##
## LEF for PtnCells ;
## created by Innovus v15.23-s045_1 on Sat Mar 22 12:44:48 2025
##

VERSION 5.8 ;

BUSBITCHARS "[]" ;
DIVIDERCHAR "/" ;

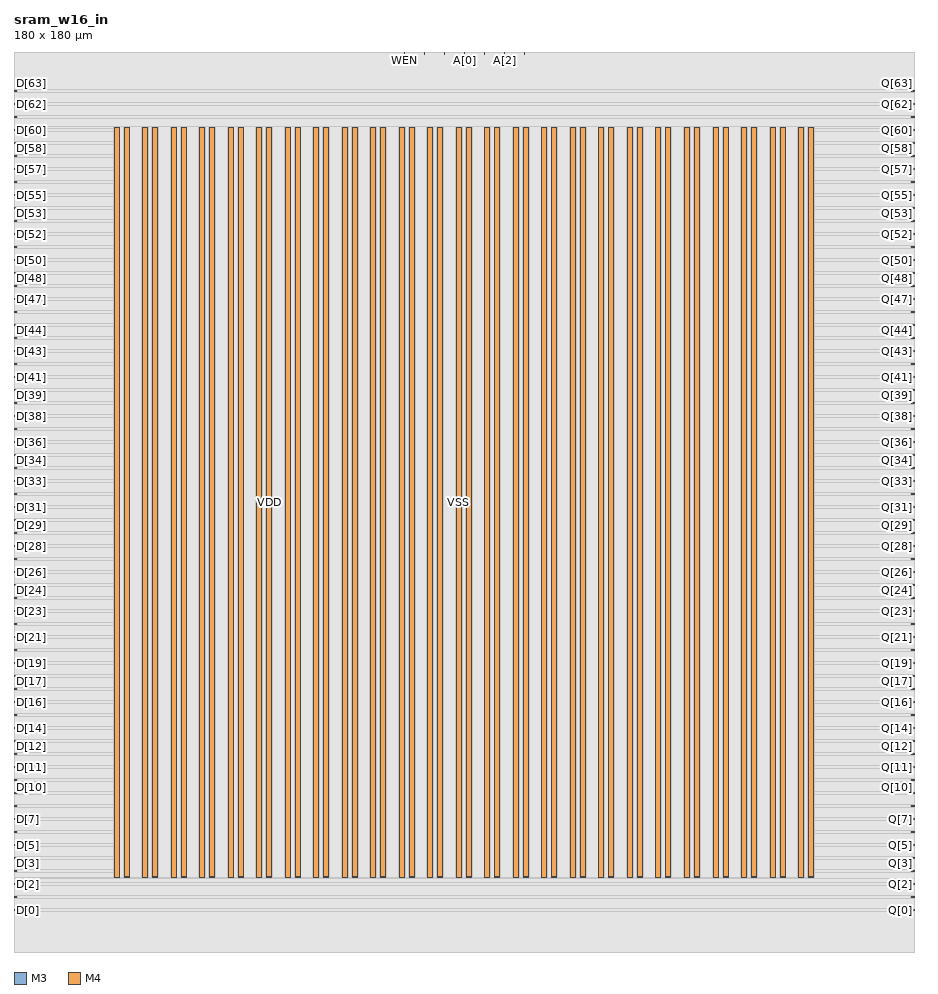
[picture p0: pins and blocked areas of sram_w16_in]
MACRO sram_w16_in
  CLASS BLOCK ;
  SIZE 180.0000 BY 180.0000 ;
  FOREIGN sram_w16_in 0.0000 0.0000 ;
  ORIGIN 0 0 ;
  SYMMETRY X Y R90 ;
  PIN clk
    DIRECTION INPUT ;
    USE SIGNAL ;
    PORT
      LAYER M3 ;
        RECT 82.0500 179.4800 82.1500 180.0000 ;
    END
  END clk
  PIN D[63]
    DIRECTION INPUT ;
    USE SIGNAL ;
    PORT
      LAYER M4 ;
        RECT 0.0000 172.1500 0.5200 172.2500 ;
    END
  END D[63]
  PIN D[62]
    DIRECTION INPUT ;
    USE SIGNAL ;
    PORT
      LAYER M4 ;
        RECT 0.0000 169.5500 0.5200 169.6500 ;
    END
  END D[62]
  PIN D[61]
    DIRECTION INPUT ;
    USE SIGNAL ;
    PORT
      LAYER M4 ;
        RECT 0.0000 166.9500 0.5200 167.0500 ;
    END
  END D[61]
  PIN D[60]
    DIRECTION INPUT ;
    USE SIGNAL ;
    PORT
      LAYER M4 ;
        RECT 0.0000 164.3500 0.5200 164.4500 ;
    END
  END D[60]
  PIN D[59]
    DIRECTION INPUT ;
    USE SIGNAL ;
    PORT
      LAYER M4 ;
        RECT 0.0000 161.7500 0.5200 161.8500 ;
    END
  END D[59]
  PIN D[58]
    DIRECTION INPUT ;
    USE SIGNAL ;
    PORT
      LAYER M4 ;
        RECT 0.0000 159.1500 0.5200 159.2500 ;
    END
  END D[58]
  PIN D[57]
    DIRECTION INPUT ;
    USE SIGNAL ;
    PORT
      LAYER M4 ;
        RECT 0.0000 156.5500 0.5200 156.6500 ;
    END
  END D[57]
  PIN D[56]
    DIRECTION INPUT ;
    USE SIGNAL ;
    PORT
      LAYER M4 ;
        RECT 0.0000 153.9500 0.5200 154.0500 ;
    END
  END D[56]
  PIN D[55]
    DIRECTION INPUT ;
    USE SIGNAL ;
    PORT
      LAYER M4 ;
        RECT 0.0000 151.3500 0.5200 151.4500 ;
    END
  END D[55]
  PIN D[54]
    DIRECTION INPUT ;
    USE SIGNAL ;
    PORT
      LAYER M4 ;
        RECT 0.0000 148.7500 0.5200 148.8500 ;
    END
  END D[54]
  PIN D[53]
    DIRECTION INPUT ;
    USE SIGNAL ;
    PORT
      LAYER M4 ;
        RECT 0.0000 146.1500 0.5200 146.2500 ;
    END
  END D[53]
  PIN D[52]
    DIRECTION INPUT ;
    USE SIGNAL ;
    PORT
      LAYER M4 ;
        RECT 0.0000 143.5500 0.5200 143.6500 ;
    END
  END D[52]
  PIN D[51]
    DIRECTION INPUT ;
    USE SIGNAL ;
    PORT
      LAYER M4 ;
        RECT 0.0000 140.9500 0.5200 141.0500 ;
    END
  END D[51]
  PIN D[50]
    DIRECTION INPUT ;
    USE SIGNAL ;
    PORT
      LAYER M4 ;
        RECT 0.0000 138.3500 0.5200 138.4500 ;
    END
  END D[50]
  PIN D[49]
    DIRECTION INPUT ;
    USE SIGNAL ;
    PORT
      LAYER M4 ;
        RECT 0.0000 135.7500 0.5200 135.8500 ;
    END
  END D[49]
  PIN D[48]
    DIRECTION INPUT ;
    USE SIGNAL ;
    PORT
      LAYER M4 ;
        RECT 0.0000 133.1500 0.5200 133.2500 ;
    END
  END D[48]
  PIN D[47]
    DIRECTION INPUT ;
    USE SIGNAL ;
    PORT
      LAYER M4 ;
        RECT 0.0000 130.5500 0.5200 130.6500 ;
    END
  END D[47]
  PIN D[46]
    DIRECTION INPUT ;
    USE SIGNAL ;
    PORT
      LAYER M4 ;
        RECT 0.0000 127.9500 0.5200 128.0500 ;
    END
  END D[46]
  PIN D[45]
    DIRECTION INPUT ;
    USE SIGNAL ;
    PORT
      LAYER M4 ;
        RECT 0.0000 125.3500 0.5200 125.4500 ;
    END
  END D[45]
  PIN D[44]
    DIRECTION INPUT ;
    USE SIGNAL ;
    PORT
      LAYER M4 ;
        RECT 0.0000 122.7500 0.5200 122.8500 ;
    END
  END D[44]
  PIN D[43]
    DIRECTION INPUT ;
    USE SIGNAL ;
    PORT
      LAYER M4 ;
        RECT 0.0000 120.1500 0.5200 120.2500 ;
    END
  END D[43]
  PIN D[42]
    DIRECTION INPUT ;
    USE SIGNAL ;
    PORT
      LAYER M4 ;
        RECT 0.0000 117.5500 0.5200 117.6500 ;
    END
  END D[42]
  PIN D[41]
    DIRECTION INPUT ;
    USE SIGNAL ;
    PORT
      LAYER M4 ;
        RECT 0.0000 114.9500 0.5200 115.0500 ;
    END
  END D[41]
  PIN D[40]
    DIRECTION INPUT ;
    USE SIGNAL ;
    PORT
      LAYER M4 ;
        RECT 0.0000 112.3500 0.5200 112.4500 ;
    END
  END D[40]
  PIN D[39]
    DIRECTION INPUT ;
    USE SIGNAL ;
    PORT
      LAYER M4 ;
        RECT 0.0000 109.7500 0.5200 109.8500 ;
    END
  END D[39]
  PIN D[38]
    DIRECTION INPUT ;
    USE SIGNAL ;
    PORT
      LAYER M4 ;
        RECT 0.0000 107.1500 0.5200 107.2500 ;
    END
  END D[38]
  PIN D[37]
    DIRECTION INPUT ;
    USE SIGNAL ;
    PORT
      LAYER M4 ;
        RECT 0.0000 104.5500 0.5200 104.6500 ;
    END
  END D[37]
  PIN D[36]
    DIRECTION INPUT ;
    USE SIGNAL ;
    PORT
      LAYER M4 ;
        RECT 0.0000 101.9500 0.5200 102.0500 ;
    END
  END D[36]
  PIN D[35]
    DIRECTION INPUT ;
    USE SIGNAL ;
    PORT
      LAYER M4 ;
        RECT 0.0000 99.3500 0.5200 99.4500 ;
    END
  END D[35]
  PIN D[34]
    DIRECTION INPUT ;
    USE SIGNAL ;
    PORT
      LAYER M4 ;
        RECT 0.0000 96.7500 0.5200 96.8500 ;
    END
  END D[34]
  PIN D[33]
    DIRECTION INPUT ;
    USE SIGNAL ;
    PORT
      LAYER M4 ;
        RECT 0.0000 94.1500 0.5200 94.2500 ;
    END
  END D[33]
  PIN D[32]
    DIRECTION INPUT ;
    USE SIGNAL ;
    PORT
      LAYER M4 ;
        RECT 0.0000 91.5500 0.5200 91.6500 ;
    END
  END D[32]
  PIN D[31]
    DIRECTION INPUT ;
    USE SIGNAL ;
    PORT
      LAYER M4 ;
        RECT 0.0000 88.9500 0.5200 89.0500 ;
    END
  END D[31]
  PIN D[30]
    DIRECTION INPUT ;
    USE SIGNAL ;
    PORT
      LAYER M4 ;
        RECT 0.0000 86.3500 0.5200 86.4500 ;
    END
  END D[30]
  PIN D[29]
    DIRECTION INPUT ;
    USE SIGNAL ;
    PORT
      LAYER M4 ;
        RECT 0.0000 83.7500 0.5200 83.8500 ;
    END
  END D[29]
  PIN D[28]
    DIRECTION INPUT ;
    USE SIGNAL ;
    PORT
      LAYER M4 ;
        RECT 0.0000 81.1500 0.5200 81.2500 ;
    END
  END D[28]
  PIN D[27]
    DIRECTION INPUT ;
    USE SIGNAL ;
    PORT
      LAYER M4 ;
        RECT 0.0000 78.5500 0.5200 78.6500 ;
    END
  END D[27]
  PIN D[26]
    DIRECTION INPUT ;
    USE SIGNAL ;
    PORT
      LAYER M4 ;
        RECT 0.0000 75.9500 0.5200 76.0500 ;
    END
  END D[26]
  PIN D[25]
    DIRECTION INPUT ;
    USE SIGNAL ;
    PORT
      LAYER M4 ;
        RECT 0.0000 73.3500 0.5200 73.4500 ;
    END
  END D[25]
  PIN D[24]
    DIRECTION INPUT ;
    USE SIGNAL ;
    PORT
      LAYER M4 ;
        RECT 0.0000 70.7500 0.5200 70.8500 ;
    END
  END D[24]
  PIN D[23]
    DIRECTION INPUT ;
    USE SIGNAL ;
    PORT
      LAYER M4 ;
        RECT 0.0000 68.1500 0.5200 68.2500 ;
    END
  END D[23]
  PIN D[22]
    DIRECTION INPUT ;
    USE SIGNAL ;
    PORT
      LAYER M4 ;
        RECT 0.0000 65.5500 0.5200 65.6500 ;
    END
  END D[22]
  PIN D[21]
    DIRECTION INPUT ;
    USE SIGNAL ;
    PORT
      LAYER M4 ;
        RECT 0.0000 62.9500 0.5200 63.0500 ;
    END
  END D[21]
  PIN D[20]
    DIRECTION INPUT ;
    USE SIGNAL ;
    PORT
      LAYER M4 ;
        RECT 0.0000 60.3500 0.5200 60.4500 ;
    END
  END D[20]
  PIN D[19]
    DIRECTION INPUT ;
    USE SIGNAL ;
    PORT
      LAYER M4 ;
        RECT 0.0000 57.7500 0.5200 57.8500 ;
    END
  END D[19]
  PIN D[18]
    DIRECTION INPUT ;
    USE SIGNAL ;
    PORT
      LAYER M4 ;
        RECT 0.0000 55.1500 0.5200 55.2500 ;
    END
  END D[18]
  PIN D[17]
    DIRECTION INPUT ;
    USE SIGNAL ;
    PORT
      LAYER M4 ;
        RECT 0.0000 52.5500 0.5200 52.6500 ;
    END
  END D[17]
  PIN D[16]
    DIRECTION INPUT ;
    USE SIGNAL ;
    PORT
      LAYER M4 ;
        RECT 0.0000 49.9500 0.5200 50.0500 ;
    END
  END D[16]
  PIN D[15]
    DIRECTION INPUT ;
    USE SIGNAL ;
    PORT
      LAYER M4 ;
        RECT 0.0000 47.3500 0.5200 47.4500 ;
    END
  END D[15]
  PIN D[14]
    DIRECTION INPUT ;
    USE SIGNAL ;
    PORT
      LAYER M4 ;
        RECT 0.0000 44.7500 0.5200 44.8500 ;
    END
  END D[14]
  PIN D[13]
    DIRECTION INPUT ;
    USE SIGNAL ;
    PORT
      LAYER M4 ;
        RECT 0.0000 42.1500 0.5200 42.2500 ;
    END
  END D[13]
  PIN D[12]
    DIRECTION INPUT ;
    USE SIGNAL ;
    PORT
      LAYER M4 ;
        RECT 0.0000 39.5500 0.5200 39.6500 ;
    END
  END D[12]
  PIN D[11]
    DIRECTION INPUT ;
    USE SIGNAL ;
    PORT
      LAYER M4 ;
        RECT 0.0000 36.9500 0.5200 37.0500 ;
    END
  END D[11]
  PIN D[10]
    DIRECTION INPUT ;
    USE SIGNAL ;
    PORT
      LAYER M4 ;
        RECT 0.0000 34.3500 0.5200 34.4500 ;
    END
  END D[10]
  PIN D[9]
    DIRECTION INPUT ;
    USE SIGNAL ;
    PORT
      LAYER M4 ;
        RECT 0.0000 31.7500 0.5200 31.8500 ;
    END
  END D[9]
  PIN D[8]
    DIRECTION INPUT ;
    USE SIGNAL ;
    PORT
      LAYER M4 ;
        RECT 0.0000 29.1500 0.5200 29.2500 ;
    END
  END D[8]
  PIN D[7]
    DIRECTION INPUT ;
    USE SIGNAL ;
    PORT
      LAYER M4 ;
        RECT 0.0000 26.5500 0.5200 26.6500 ;
    END
  END D[7]
  PIN D[6]
    DIRECTION INPUT ;
    USE SIGNAL ;
    PORT
      LAYER M4 ;
        RECT 0.0000 23.9500 0.5200 24.0500 ;
    END
  END D[6]
  PIN D[5]
    DIRECTION INPUT ;
    USE SIGNAL ;
    PORT
      LAYER M4 ;
        RECT 0.0000 21.3500 0.5200 21.4500 ;
    END
  END D[5]
  PIN D[4]
    DIRECTION INPUT ;
    USE SIGNAL ;
    PORT
      LAYER M4 ;
        RECT 0.0000 18.7500 0.5200 18.8500 ;
    END
  END D[4]
  PIN D[3]
    DIRECTION INPUT ;
    USE SIGNAL ;
    PORT
      LAYER M4 ;
        RECT 0.0000 16.1500 0.5200 16.2500 ;
    END
  END D[3]
  PIN D[2]
    DIRECTION INPUT ;
    USE SIGNAL ;
    PORT
      LAYER M4 ;
        RECT 0.0000 13.5500 0.5200 13.6500 ;
    END
  END D[2]
  PIN D[1]
    DIRECTION INPUT ;
    USE SIGNAL ;
    PORT
      LAYER M4 ;
        RECT 0.0000 10.9500 0.5200 11.0500 ;
    END
  END D[1]
  PIN D[0]
    DIRECTION INPUT ;
    USE SIGNAL ;
    PORT
      LAYER M4 ;
        RECT 0.0000 8.3500 0.5200 8.4500 ;
    END
  END D[0]
  PIN Q[63]
    DIRECTION OUTPUT ;
    USE SIGNAL ;
    PORT
      LAYER M4 ;
        RECT 179.4800 172.1500 180.0000 172.2500 ;
    END
  END Q[63]
  PIN Q[62]
    DIRECTION OUTPUT ;
    USE SIGNAL ;
    PORT
      LAYER M4 ;
        RECT 179.4800 169.5500 180.0000 169.6500 ;
    END
  END Q[62]
  PIN Q[61]
    DIRECTION OUTPUT ;
    USE SIGNAL ;
    PORT
      LAYER M4 ;
        RECT 179.4800 166.9500 180.0000 167.0500 ;
    END
  END Q[61]
  PIN Q[60]
    DIRECTION OUTPUT ;
    USE SIGNAL ;
    PORT
      LAYER M4 ;
        RECT 179.4800 164.3500 180.0000 164.4500 ;
    END
  END Q[60]
  PIN Q[59]
    DIRECTION OUTPUT ;
    USE SIGNAL ;
    PORT
      LAYER M4 ;
        RECT 179.4800 161.7500 180.0000 161.8500 ;
    END
  END Q[59]
  PIN Q[58]
    DIRECTION OUTPUT ;
    USE SIGNAL ;
    PORT
      LAYER M4 ;
        RECT 179.4800 159.1500 180.0000 159.2500 ;
    END
  END Q[58]
  PIN Q[57]
    DIRECTION OUTPUT ;
    USE SIGNAL ;
    PORT
      LAYER M4 ;
        RECT 179.4800 156.5500 180.0000 156.6500 ;
    END
  END Q[57]
  PIN Q[56]
    DIRECTION OUTPUT ;
    USE SIGNAL ;
    PORT
      LAYER M4 ;
        RECT 179.4800 153.9500 180.0000 154.0500 ;
    END
  END Q[56]
  PIN Q[55]
    DIRECTION OUTPUT ;
    USE SIGNAL ;
    PORT
      LAYER M4 ;
        RECT 179.4800 151.3500 180.0000 151.4500 ;
    END
  END Q[55]
  PIN Q[54]
    DIRECTION OUTPUT ;
    USE SIGNAL ;
    PORT
      LAYER M4 ;
        RECT 179.4800 148.7500 180.0000 148.8500 ;
    END
  END Q[54]
  PIN Q[53]
    DIRECTION OUTPUT ;
    USE SIGNAL ;
    PORT
      LAYER M4 ;
        RECT 179.4800 146.1500 180.0000 146.2500 ;
    END
  END Q[53]
  PIN Q[52]
    DIRECTION OUTPUT ;
    USE SIGNAL ;
    PORT
      LAYER M4 ;
        RECT 179.4800 143.5500 180.0000 143.6500 ;
    END
  END Q[52]
  PIN Q[51]
    DIRECTION OUTPUT ;
    USE SIGNAL ;
    PORT
      LAYER M4 ;
        RECT 179.4800 140.9500 180.0000 141.0500 ;
    END
  END Q[51]
  PIN Q[50]
    DIRECTION OUTPUT ;
    USE SIGNAL ;
    PORT
      LAYER M4 ;
        RECT 179.4800 138.3500 180.0000 138.4500 ;
    END
  END Q[50]
  PIN Q[49]
    DIRECTION OUTPUT ;
    USE SIGNAL ;
    PORT
      LAYER M4 ;
        RECT 179.4800 135.7500 180.0000 135.8500 ;
    END
  END Q[49]
  PIN Q[48]
    DIRECTION OUTPUT ;
    USE SIGNAL ;
    PORT
      LAYER M4 ;
        RECT 179.4800 133.1500 180.0000 133.2500 ;
    END
  END Q[48]
  PIN Q[47]
    DIRECTION OUTPUT ;
    USE SIGNAL ;
    PORT
      LAYER M4 ;
        RECT 179.4800 130.5500 180.0000 130.6500 ;
    END
  END Q[47]
  PIN Q[46]
    DIRECTION OUTPUT ;
    USE SIGNAL ;
    PORT
      LAYER M4 ;
        RECT 179.4800 127.9500 180.0000 128.0500 ;
    END
  END Q[46]
  PIN Q[45]
    DIRECTION OUTPUT ;
    USE SIGNAL ;
    PORT
      LAYER M4 ;
        RECT 179.4800 125.3500 180.0000 125.4500 ;
    END
  END Q[45]
  PIN Q[44]
    DIRECTION OUTPUT ;
    USE SIGNAL ;
    PORT
      LAYER M4 ;
        RECT 179.4800 122.7500 180.0000 122.8500 ;
    END
  END Q[44]
  PIN Q[43]
    DIRECTION OUTPUT ;
    USE SIGNAL ;
    PORT
      LAYER M4 ;
        RECT 179.4800 120.1500 180.0000 120.2500 ;
    END
  END Q[43]
  PIN Q[42]
    DIRECTION OUTPUT ;
    USE SIGNAL ;
    PORT
      LAYER M4 ;
        RECT 179.4800 117.5500 180.0000 117.6500 ;
    END
  END Q[42]
  PIN Q[41]
    DIRECTION OUTPUT ;
    USE SIGNAL ;
    PORT
      LAYER M4 ;
        RECT 179.4800 114.9500 180.0000 115.0500 ;
    END
  END Q[41]
  PIN Q[40]
    DIRECTION OUTPUT ;
    USE SIGNAL ;
    PORT
      LAYER M4 ;
        RECT 179.4800 112.3500 180.0000 112.4500 ;
    END
  END Q[40]
  PIN Q[39]
    DIRECTION OUTPUT ;
    USE SIGNAL ;
    PORT
      LAYER M4 ;
        RECT 179.4800 109.7500 180.0000 109.8500 ;
    END
  END Q[39]
  PIN Q[38]
    DIRECTION OUTPUT ;
    USE SIGNAL ;
    PORT
      LAYER M4 ;
        RECT 179.4800 107.1500 180.0000 107.2500 ;
    END
  END Q[38]
  PIN Q[37]
    DIRECTION OUTPUT ;
    USE SIGNAL ;
    PORT
      LAYER M4 ;
        RECT 179.4800 104.5500 180.0000 104.6500 ;
    END
  END Q[37]
  PIN Q[36]
    DIRECTION OUTPUT ;
    USE SIGNAL ;
    PORT
      LAYER M4 ;
        RECT 179.4800 101.9500 180.0000 102.0500 ;
    END
  END Q[36]
  PIN Q[35]
    DIRECTION OUTPUT ;
    USE SIGNAL ;
    PORT
      LAYER M4 ;
        RECT 179.4800 99.3500 180.0000 99.4500 ;
    END
  END Q[35]
  PIN Q[34]
    DIRECTION OUTPUT ;
    USE SIGNAL ;
    PORT
      LAYER M4 ;
        RECT 179.4800 96.7500 180.0000 96.8500 ;
    END
  END Q[34]
  PIN Q[33]
    DIRECTION OUTPUT ;
    USE SIGNAL ;
    PORT
      LAYER M4 ;
        RECT 179.4800 94.1500 180.0000 94.2500 ;
    END
  END Q[33]
  PIN Q[32]
    DIRECTION OUTPUT ;
    USE SIGNAL ;
    PORT
      LAYER M4 ;
        RECT 179.4800 91.5500 180.0000 91.6500 ;
    END
  END Q[32]
  PIN Q[31]
    DIRECTION OUTPUT ;
    USE SIGNAL ;
    PORT
      LAYER M4 ;
        RECT 179.4800 88.9500 180.0000 89.0500 ;
    END
  END Q[31]
  PIN Q[30]
    DIRECTION OUTPUT ;
    USE SIGNAL ;
    PORT
      LAYER M4 ;
        RECT 179.4800 86.3500 180.0000 86.4500 ;
    END
  END Q[30]
  PIN Q[29]
    DIRECTION OUTPUT ;
    USE SIGNAL ;
    PORT
      LAYER M4 ;
        RECT 179.4800 83.7500 180.0000 83.8500 ;
    END
  END Q[29]
  PIN Q[28]
    DIRECTION OUTPUT ;
    USE SIGNAL ;
    PORT
      LAYER M4 ;
        RECT 179.4800 81.1500 180.0000 81.2500 ;
    END
  END Q[28]
  PIN Q[27]
    DIRECTION OUTPUT ;
    USE SIGNAL ;
    PORT
      LAYER M4 ;
        RECT 179.4800 78.5500 180.0000 78.6500 ;
    END
  END Q[27]
  PIN Q[26]
    DIRECTION OUTPUT ;
    USE SIGNAL ;
    PORT
      LAYER M4 ;
        RECT 179.4800 75.9500 180.0000 76.0500 ;
    END
  END Q[26]
  PIN Q[25]
    DIRECTION OUTPUT ;
    USE SIGNAL ;
    PORT
      LAYER M4 ;
        RECT 179.4800 73.3500 180.0000 73.4500 ;
    END
  END Q[25]
  PIN Q[24]
    DIRECTION OUTPUT ;
    USE SIGNAL ;
    PORT
      LAYER M4 ;
        RECT 179.4800 70.7500 180.0000 70.8500 ;
    END
  END Q[24]
  PIN Q[23]
    DIRECTION OUTPUT ;
    USE SIGNAL ;
    PORT
      LAYER M4 ;
        RECT 179.4800 68.1500 180.0000 68.2500 ;
    END
  END Q[23]
  PIN Q[22]
    DIRECTION OUTPUT ;
    USE SIGNAL ;
    PORT
      LAYER M4 ;
        RECT 179.4800 65.5500 180.0000 65.6500 ;
    END
  END Q[22]
  PIN Q[21]
    DIRECTION OUTPUT ;
    USE SIGNAL ;
    PORT
      LAYER M4 ;
        RECT 179.4800 62.9500 180.0000 63.0500 ;
    END
  END Q[21]
  PIN Q[20]
    DIRECTION OUTPUT ;
    USE SIGNAL ;
    PORT
      LAYER M4 ;
        RECT 179.4800 60.3500 180.0000 60.4500 ;
    END
  END Q[20]
  PIN Q[19]
    DIRECTION OUTPUT ;
    USE SIGNAL ;
    PORT
      LAYER M4 ;
        RECT 179.4800 57.7500 180.0000 57.8500 ;
    END
  END Q[19]
  PIN Q[18]
    DIRECTION OUTPUT ;
    USE SIGNAL ;
    PORT
      LAYER M4 ;
        RECT 179.4800 55.1500 180.0000 55.2500 ;
    END
  END Q[18]
  PIN Q[17]
    DIRECTION OUTPUT ;
    USE SIGNAL ;
    PORT
      LAYER M4 ;
        RECT 179.4800 52.5500 180.0000 52.6500 ;
    END
  END Q[17]
  PIN Q[16]
    DIRECTION OUTPUT ;
    USE SIGNAL ;
    PORT
      LAYER M4 ;
        RECT 179.4800 49.9500 180.0000 50.0500 ;
    END
  END Q[16]
  PIN Q[15]
    DIRECTION OUTPUT ;
    USE SIGNAL ;
    PORT
      LAYER M4 ;
        RECT 179.4800 47.3500 180.0000 47.4500 ;
    END
  END Q[15]
  PIN Q[14]
    DIRECTION OUTPUT ;
    USE SIGNAL ;
    PORT
      LAYER M4 ;
        RECT 179.4800 44.7500 180.0000 44.8500 ;
    END
  END Q[14]
  PIN Q[13]
    DIRECTION OUTPUT ;
    USE SIGNAL ;
    PORT
      LAYER M4 ;
        RECT 179.4800 42.1500 180.0000 42.2500 ;
    END
  END Q[13]
  PIN Q[12]
    DIRECTION OUTPUT ;
    USE SIGNAL ;
    PORT
      LAYER M4 ;
        RECT 179.4800 39.5500 180.0000 39.6500 ;
    END
  END Q[12]
  PIN Q[11]
    DIRECTION OUTPUT ;
    USE SIGNAL ;
    PORT
      LAYER M4 ;
        RECT 179.4800 36.9500 180.0000 37.0500 ;
    END
  END Q[11]
  PIN Q[10]
    DIRECTION OUTPUT ;
    USE SIGNAL ;
    PORT
      LAYER M4 ;
        RECT 179.4800 34.3500 180.0000 34.4500 ;
    END
  END Q[10]
  PIN Q[9]
    DIRECTION OUTPUT ;
    USE SIGNAL ;
    PORT
      LAYER M4 ;
        RECT 179.4800 31.7500 180.0000 31.8500 ;
    END
  END Q[9]
  PIN Q[8]
    DIRECTION OUTPUT ;
    USE SIGNAL ;
    PORT
      LAYER M4 ;
        RECT 179.4800 29.1500 180.0000 29.2500 ;
    END
  END Q[8]
  PIN Q[7]
    DIRECTION OUTPUT ;
    USE SIGNAL ;
    PORT
      LAYER M4 ;
        RECT 179.4800 26.5500 180.0000 26.6500 ;
    END
  END Q[7]
  PIN Q[6]
    DIRECTION OUTPUT ;
    USE SIGNAL ;
    PORT
      LAYER M4 ;
        RECT 179.4800 23.9500 180.0000 24.0500 ;
    END
  END Q[6]
  PIN Q[5]
    DIRECTION OUTPUT ;
    USE SIGNAL ;
    PORT
      LAYER M4 ;
        RECT 179.4800 21.3500 180.0000 21.4500 ;
    END
  END Q[5]
  PIN Q[4]
    DIRECTION OUTPUT ;
    USE SIGNAL ;
    PORT
      LAYER M4 ;
        RECT 179.4800 18.7500 180.0000 18.8500 ;
    END
  END Q[4]
  PIN Q[3]
    DIRECTION OUTPUT ;
    USE SIGNAL ;
    PORT
      LAYER M4 ;
        RECT 179.4800 16.1500 180.0000 16.2500 ;
    END
  END Q[3]
  PIN Q[2]
    DIRECTION OUTPUT ;
    USE SIGNAL ;
    PORT
      LAYER M4 ;
        RECT 179.4800 13.5500 180.0000 13.6500 ;
    END
  END Q[2]
  PIN Q[1]
    DIRECTION OUTPUT ;
    USE SIGNAL ;
    PORT
      LAYER M4 ;
        RECT 179.4800 10.9500 180.0000 11.0500 ;
    END
  END Q[1]
  PIN Q[0]
    DIRECTION OUTPUT ;
    USE SIGNAL ;
    PORT
      LAYER M4 ;
        RECT 179.4800 8.3500 180.0000 8.4500 ;
    END
  END Q[0]
  PIN CEN
    DIRECTION INPUT ;
    USE SIGNAL ;
    PORT
      LAYER M3 ;
        RECT 86.0500 179.4800 86.1500 180.0000 ;
    END
  END CEN
  PIN WEN
    DIRECTION INPUT ;
    USE SIGNAL ;
    PORT
      LAYER M3 ;
        RECT 78.0500 179.4800 78.1500 180.0000 ;
    END
  END WEN
  PIN A[3]
    DIRECTION INPUT ;
    USE SIGNAL ;
    PORT
      LAYER M3 ;
        RECT 102.0500 179.4800 102.1500 180.0000 ;
    END
  END A[3]
  PIN A[2]
    DIRECTION INPUT ;
    USE SIGNAL ;
    PORT
      LAYER M3 ;
        RECT 98.0500 179.4800 98.1500 180.0000 ;
    END
  END A[2]
  PIN A[1]
    DIRECTION INPUT ;
    USE SIGNAL ;
    PORT
      LAYER M3 ;
        RECT 94.0500 179.4800 94.1500 180.0000 ;
    END
  END A[1]
  PIN A[0]
    DIRECTION INPUT ;
    USE SIGNAL ;
    PORT
      LAYER M3 ;
        RECT 90.0500 179.4800 90.1500 180.0000 ;
    END
  END A[0]
  PIN VSS
    DIRECTION INOUT ;
    USE GROUND ;

# P/G power stripe data as pin
    PORT
      LAYER M4 ;
        RECT 88.4600 15.0000 89.4600 165.0000 ;
        RECT 82.7550 15.0000 83.7550 165.0000 ;
        RECT 77.0500 15.0000 78.0500 165.0000 ;
        RECT 71.3450 15.0000 72.3450 165.0000 ;
        RECT 65.6400 15.0000 66.6400 165.0000 ;
        RECT 59.9350 15.0000 60.9350 165.0000 ;
        RECT 54.2300 15.0000 55.2300 165.0000 ;
        RECT 48.5250 15.0000 49.5250 165.0000 ;
        RECT 42.8200 15.0000 43.8200 165.0000 ;
        RECT 37.1150 15.0000 38.1150 165.0000 ;
        RECT 31.4100 15.0000 32.4100 165.0000 ;
        RECT 25.7050 15.0000 26.7050 165.0000 ;
        RECT 20.0000 15.0000 21.0000 165.0000 ;
        RECT 156.9200 15.0000 157.9200 165.0000 ;
        RECT 151.2150 15.0000 152.2150 165.0000 ;
        RECT 145.5100 15.0000 146.5100 165.0000 ;
        RECT 139.8050 15.0000 140.8050 165.0000 ;
        RECT 134.1000 15.0000 135.1000 165.0000 ;
        RECT 128.3950 15.0000 129.3950 165.0000 ;
        RECT 122.6900 15.0000 123.6900 165.0000 ;
        RECT 116.9850 15.0000 117.9850 165.0000 ;
        RECT 111.2800 15.0000 112.2800 165.0000 ;
        RECT 105.5750 15.0000 106.5750 165.0000 ;
        RECT 99.8700 15.0000 100.8700 165.0000 ;
        RECT 94.1650 15.0000 95.1650 165.0000 ;
    END
# end of P/G power stripe data as pin

  END VSS
  PIN VDD
    DIRECTION INOUT ;
    USE POWER ;

# P/G power stripe data as pin
    PORT
      LAYER M4 ;
        RECT 50.5250 15.0000 51.5250 165.0000 ;
        RECT 44.8200 15.0000 45.8200 165.0000 ;
        RECT 39.1150 15.0000 40.1150 165.0000 ;
        RECT 33.4100 15.0000 34.4100 165.0000 ;
        RECT 27.7050 15.0000 28.7050 165.0000 ;
        RECT 22.0000 15.0000 23.0000 165.0000 ;
        RECT 56.2300 15.0000 57.2300 165.0000 ;
        RECT 61.9350 15.0000 62.9350 165.0000 ;
        RECT 67.6400 15.0000 68.6400 165.0000 ;
        RECT 73.3450 15.0000 74.3450 165.0000 ;
        RECT 79.0500 15.0000 80.0500 165.0000 ;
        RECT 84.7550 15.0000 85.7550 165.0000 ;
        RECT 90.4600 15.0000 91.4600 165.0000 ;
        RECT 96.1650 15.0000 97.1650 165.0000 ;
        RECT 101.8700 15.0000 102.8700 165.0000 ;
        RECT 107.5750 15.0000 108.5750 165.0000 ;
        RECT 113.2800 15.0000 114.2800 165.0000 ;
        RECT 118.9850 15.0000 119.9850 165.0000 ;
        RECT 124.6900 15.0000 125.6900 165.0000 ;
        RECT 130.3950 15.0000 131.3950 165.0000 ;
        RECT 136.1000 15.0000 137.1000 165.0000 ;
        RECT 141.8050 15.0000 142.8050 165.0000 ;
        RECT 147.5100 15.0000 148.5100 165.0000 ;
        RECT 153.2150 15.0000 154.2150 165.0000 ;
        RECT 158.9200 15.0000 159.9200 165.0000 ;
        RECT 44.8200 14.8350 45.8200 15.1650 ;
        RECT 22.0000 14.8350 23.0000 15.1650 ;
        RECT 33.4100 14.8350 34.4100 15.1650 ;
        RECT 27.7050 14.8350 28.7050 15.1650 ;
        RECT 39.1150 14.8350 40.1150 15.1650 ;
        RECT 56.2300 14.8350 57.2300 15.1650 ;
        RECT 50.5250 14.8350 51.5250 15.1650 ;
        RECT 61.9350 14.8350 62.9350 15.1650 ;
        RECT 73.3450 14.8350 74.3450 15.1650 ;
        RECT 67.6400 14.8350 68.6400 15.1650 ;
        RECT 84.7550 14.8350 85.7550 15.1650 ;
        RECT 79.0500 14.8350 80.0500 15.1650 ;
        RECT 96.1650 14.8350 97.1650 15.1650 ;
        RECT 90.4600 14.8350 91.4600 15.1650 ;
        RECT 107.5750 14.8350 108.5750 15.1650 ;
        RECT 101.8700 14.8350 102.8700 15.1650 ;
        RECT 118.9850 14.8350 119.9850 15.1650 ;
        RECT 113.2800 14.8350 114.2800 15.1650 ;
        RECT 130.3950 14.8350 131.3950 15.1650 ;
        RECT 124.6900 14.8350 125.6900 15.1650 ;
        RECT 141.8050 14.8350 142.8050 15.1650 ;
        RECT 136.1000 14.8350 137.1000 15.1650 ;
        RECT 153.2150 14.8350 154.2150 15.1650 ;
        RECT 147.5100 14.8350 148.5100 15.1650 ;
        RECT 158.9200 14.8350 159.9200 15.1650 ;
    END
# end of P/G power stripe data as pin

  END VDD
  OBS
    LAYER M1 ;
      RECT 0.0000 0.0000 180.0000 180.0000 ;
    LAYER M2 ;
      RECT 0.0000 0.0000 180.0000 180.0000 ;
    LAYER M3 ;
      RECT 102.3100 179.3200 180.0000 180.0000 ;
      RECT 98.3100 179.3200 101.8900 180.0000 ;
      RECT 94.3100 179.3200 97.8900 180.0000 ;
      RECT 90.3100 179.3200 93.8900 180.0000 ;
      RECT 86.3100 179.3200 89.8900 180.0000 ;
      RECT 82.3100 179.3200 85.8900 180.0000 ;
      RECT 78.3100 179.3200 81.8900 180.0000 ;
      RECT 0.0000 179.3200 77.8900 180.0000 ;
      RECT 0.0000 0.0000 180.0000 179.3200 ;
    LAYER M4 ;
      RECT 0.0000 172.4100 180.0000 180.0000 ;
      RECT 0.6800 171.9900 179.3200 172.4100 ;
      RECT 0.0000 169.8100 180.0000 171.9900 ;
      RECT 0.6800 169.3900 179.3200 169.8100 ;
      RECT 0.0000 167.2100 180.0000 169.3900 ;
      RECT 0.6800 166.7900 179.3200 167.2100 ;
      RECT 0.0000 165.1600 180.0000 166.7900 ;
      RECT 160.0800 164.6100 180.0000 165.1600 ;
      RECT 0.0000 164.6100 19.8400 165.1600 ;
      RECT 160.0800 164.1900 179.3200 164.6100 ;
      RECT 0.6800 164.1900 19.8400 164.6100 ;
      RECT 160.0800 162.0100 180.0000 164.1900 ;
      RECT 0.0000 162.0100 19.8400 164.1900 ;
      RECT 160.0800 161.5900 179.3200 162.0100 ;
      RECT 0.6800 161.5900 19.8400 162.0100 ;
      RECT 160.0800 159.4100 180.0000 161.5900 ;
      RECT 0.0000 159.4100 19.8400 161.5900 ;
      RECT 160.0800 158.9900 179.3200 159.4100 ;
      RECT 0.6800 158.9900 19.8400 159.4100 ;
      RECT 160.0800 156.8100 180.0000 158.9900 ;
      RECT 0.0000 156.8100 19.8400 158.9900 ;
      RECT 160.0800 156.3900 179.3200 156.8100 ;
      RECT 0.6800 156.3900 19.8400 156.8100 ;
      RECT 160.0800 154.2100 180.0000 156.3900 ;
      RECT 0.0000 154.2100 19.8400 156.3900 ;
      RECT 160.0800 153.7900 179.3200 154.2100 ;
      RECT 0.6800 153.7900 19.8400 154.2100 ;
      RECT 160.0800 151.6100 180.0000 153.7900 ;
      RECT 0.0000 151.6100 19.8400 153.7900 ;
      RECT 160.0800 151.1900 179.3200 151.6100 ;
      RECT 0.6800 151.1900 19.8400 151.6100 ;
      RECT 160.0800 149.0100 180.0000 151.1900 ;
      RECT 0.0000 149.0100 19.8400 151.1900 ;
      RECT 160.0800 148.5900 179.3200 149.0100 ;
      RECT 0.6800 148.5900 19.8400 149.0100 ;
      RECT 160.0800 146.4100 180.0000 148.5900 ;
      RECT 0.0000 146.4100 19.8400 148.5900 ;
      RECT 160.0800 145.9900 179.3200 146.4100 ;
      RECT 0.6800 145.9900 19.8400 146.4100 ;
      RECT 160.0800 143.8100 180.0000 145.9900 ;
      RECT 0.0000 143.8100 19.8400 145.9900 ;
      RECT 160.0800 143.3900 179.3200 143.8100 ;
      RECT 0.6800 143.3900 19.8400 143.8100 ;
      RECT 160.0800 141.2100 180.0000 143.3900 ;
      RECT 0.0000 141.2100 19.8400 143.3900 ;
      RECT 160.0800 140.7900 179.3200 141.2100 ;
      RECT 0.6800 140.7900 19.8400 141.2100 ;
      RECT 160.0800 138.6100 180.0000 140.7900 ;
      RECT 0.0000 138.6100 19.8400 140.7900 ;
      RECT 160.0800 138.1900 179.3200 138.6100 ;
      RECT 0.6800 138.1900 19.8400 138.6100 ;
      RECT 160.0800 136.0100 180.0000 138.1900 ;
      RECT 0.0000 136.0100 19.8400 138.1900 ;
      RECT 160.0800 135.5900 179.3200 136.0100 ;
      RECT 0.6800 135.5900 19.8400 136.0100 ;
      RECT 160.0800 133.4100 180.0000 135.5900 ;
      RECT 0.0000 133.4100 19.8400 135.5900 ;
      RECT 160.0800 132.9900 179.3200 133.4100 ;
      RECT 0.6800 132.9900 19.8400 133.4100 ;
      RECT 160.0800 130.8100 180.0000 132.9900 ;
      RECT 0.0000 130.8100 19.8400 132.9900 ;
      RECT 160.0800 130.3900 179.3200 130.8100 ;
      RECT 0.6800 130.3900 19.8400 130.8100 ;
      RECT 160.0800 128.2100 180.0000 130.3900 ;
      RECT 0.0000 128.2100 19.8400 130.3900 ;
      RECT 160.0800 127.7900 179.3200 128.2100 ;
      RECT 0.6800 127.7900 19.8400 128.2100 ;
      RECT 160.0800 125.6100 180.0000 127.7900 ;
      RECT 0.0000 125.6100 19.8400 127.7900 ;
      RECT 160.0800 125.1900 179.3200 125.6100 ;
      RECT 0.6800 125.1900 19.8400 125.6100 ;
      RECT 160.0800 123.0100 180.0000 125.1900 ;
      RECT 0.0000 123.0100 19.8400 125.1900 ;
      RECT 160.0800 122.5900 179.3200 123.0100 ;
      RECT 0.6800 122.5900 19.8400 123.0100 ;
      RECT 160.0800 120.4100 180.0000 122.5900 ;
      RECT 0.0000 120.4100 19.8400 122.5900 ;
      RECT 160.0800 119.9900 179.3200 120.4100 ;
      RECT 0.6800 119.9900 19.8400 120.4100 ;
      RECT 160.0800 117.8100 180.0000 119.9900 ;
      RECT 0.0000 117.8100 19.8400 119.9900 ;
      RECT 160.0800 117.3900 179.3200 117.8100 ;
      RECT 0.6800 117.3900 19.8400 117.8100 ;
      RECT 160.0800 115.2100 180.0000 117.3900 ;
      RECT 0.0000 115.2100 19.8400 117.3900 ;
      RECT 160.0800 114.7900 179.3200 115.2100 ;
      RECT 0.6800 114.7900 19.8400 115.2100 ;
      RECT 160.0800 112.6100 180.0000 114.7900 ;
      RECT 0.0000 112.6100 19.8400 114.7900 ;
      RECT 160.0800 112.1900 179.3200 112.6100 ;
      RECT 0.6800 112.1900 19.8400 112.6100 ;
      RECT 160.0800 110.0100 180.0000 112.1900 ;
      RECT 0.0000 110.0100 19.8400 112.1900 ;
      RECT 160.0800 109.5900 179.3200 110.0100 ;
      RECT 0.6800 109.5900 19.8400 110.0100 ;
      RECT 160.0800 107.4100 180.0000 109.5900 ;
      RECT 0.0000 107.4100 19.8400 109.5900 ;
      RECT 160.0800 106.9900 179.3200 107.4100 ;
      RECT 0.6800 106.9900 19.8400 107.4100 ;
      RECT 160.0800 104.8100 180.0000 106.9900 ;
      RECT 0.0000 104.8100 19.8400 106.9900 ;
      RECT 160.0800 104.3900 179.3200 104.8100 ;
      RECT 0.6800 104.3900 19.8400 104.8100 ;
      RECT 160.0800 102.2100 180.0000 104.3900 ;
      RECT 0.0000 102.2100 19.8400 104.3900 ;
      RECT 160.0800 101.7900 179.3200 102.2100 ;
      RECT 0.6800 101.7900 19.8400 102.2100 ;
      RECT 160.0800 99.6100 180.0000 101.7900 ;
      RECT 0.0000 99.6100 19.8400 101.7900 ;
      RECT 160.0800 99.1900 179.3200 99.6100 ;
      RECT 0.6800 99.1900 19.8400 99.6100 ;
      RECT 160.0800 97.0100 180.0000 99.1900 ;
      RECT 0.0000 97.0100 19.8400 99.1900 ;
      RECT 160.0800 96.5900 179.3200 97.0100 ;
      RECT 0.6800 96.5900 19.8400 97.0100 ;
      RECT 160.0800 94.4100 180.0000 96.5900 ;
      RECT 0.0000 94.4100 19.8400 96.5900 ;
      RECT 160.0800 93.9900 179.3200 94.4100 ;
      RECT 0.6800 93.9900 19.8400 94.4100 ;
      RECT 160.0800 91.8100 180.0000 93.9900 ;
      RECT 0.0000 91.8100 19.8400 93.9900 ;
      RECT 160.0800 91.3900 179.3200 91.8100 ;
      RECT 0.6800 91.3900 19.8400 91.8100 ;
      RECT 160.0800 89.2100 180.0000 91.3900 ;
      RECT 0.0000 89.2100 19.8400 91.3900 ;
      RECT 160.0800 88.7900 179.3200 89.2100 ;
      RECT 0.6800 88.7900 19.8400 89.2100 ;
      RECT 160.0800 86.6100 180.0000 88.7900 ;
      RECT 0.0000 86.6100 19.8400 88.7900 ;
      RECT 160.0800 86.1900 179.3200 86.6100 ;
      RECT 0.6800 86.1900 19.8400 86.6100 ;
      RECT 160.0800 84.0100 180.0000 86.1900 ;
      RECT 0.0000 84.0100 19.8400 86.1900 ;
      RECT 160.0800 83.5900 179.3200 84.0100 ;
      RECT 0.6800 83.5900 19.8400 84.0100 ;
      RECT 160.0800 81.4100 180.0000 83.5900 ;
      RECT 0.0000 81.4100 19.8400 83.5900 ;
      RECT 160.0800 80.9900 179.3200 81.4100 ;
      RECT 0.6800 80.9900 19.8400 81.4100 ;
      RECT 160.0800 78.8100 180.0000 80.9900 ;
      RECT 0.0000 78.8100 19.8400 80.9900 ;
      RECT 160.0800 78.3900 179.3200 78.8100 ;
      RECT 0.6800 78.3900 19.8400 78.8100 ;
      RECT 160.0800 76.2100 180.0000 78.3900 ;
      RECT 0.0000 76.2100 19.8400 78.3900 ;
      RECT 160.0800 75.7900 179.3200 76.2100 ;
      RECT 0.6800 75.7900 19.8400 76.2100 ;
      RECT 160.0800 73.6100 180.0000 75.7900 ;
      RECT 0.0000 73.6100 19.8400 75.7900 ;
      RECT 160.0800 73.1900 179.3200 73.6100 ;
      RECT 0.6800 73.1900 19.8400 73.6100 ;
      RECT 160.0800 71.0100 180.0000 73.1900 ;
      RECT 0.0000 71.0100 19.8400 73.1900 ;
      RECT 160.0800 70.5900 179.3200 71.0100 ;
      RECT 0.6800 70.5900 19.8400 71.0100 ;
      RECT 160.0800 68.4100 180.0000 70.5900 ;
      RECT 0.0000 68.4100 19.8400 70.5900 ;
      RECT 160.0800 67.9900 179.3200 68.4100 ;
      RECT 0.6800 67.9900 19.8400 68.4100 ;
      RECT 160.0800 65.8100 180.0000 67.9900 ;
      RECT 0.0000 65.8100 19.8400 67.9900 ;
      RECT 160.0800 65.3900 179.3200 65.8100 ;
      RECT 0.6800 65.3900 19.8400 65.8100 ;
      RECT 160.0800 63.2100 180.0000 65.3900 ;
      RECT 0.0000 63.2100 19.8400 65.3900 ;
      RECT 160.0800 62.7900 179.3200 63.2100 ;
      RECT 0.6800 62.7900 19.8400 63.2100 ;
      RECT 160.0800 60.6100 180.0000 62.7900 ;
      RECT 0.0000 60.6100 19.8400 62.7900 ;
      RECT 160.0800 60.1900 179.3200 60.6100 ;
      RECT 0.6800 60.1900 19.8400 60.6100 ;
      RECT 160.0800 58.0100 180.0000 60.1900 ;
      RECT 0.0000 58.0100 19.8400 60.1900 ;
      RECT 160.0800 57.5900 179.3200 58.0100 ;
      RECT 0.6800 57.5900 19.8400 58.0100 ;
      RECT 160.0800 55.4100 180.0000 57.5900 ;
      RECT 0.0000 55.4100 19.8400 57.5900 ;
      RECT 160.0800 54.9900 179.3200 55.4100 ;
      RECT 0.6800 54.9900 19.8400 55.4100 ;
      RECT 160.0800 52.8100 180.0000 54.9900 ;
      RECT 0.0000 52.8100 19.8400 54.9900 ;
      RECT 160.0800 52.3900 179.3200 52.8100 ;
      RECT 0.6800 52.3900 19.8400 52.8100 ;
      RECT 160.0800 50.2100 180.0000 52.3900 ;
      RECT 0.0000 50.2100 19.8400 52.3900 ;
      RECT 160.0800 49.7900 179.3200 50.2100 ;
      RECT 0.6800 49.7900 19.8400 50.2100 ;
      RECT 160.0800 47.6100 180.0000 49.7900 ;
      RECT 0.0000 47.6100 19.8400 49.7900 ;
      RECT 160.0800 47.1900 179.3200 47.6100 ;
      RECT 0.6800 47.1900 19.8400 47.6100 ;
      RECT 160.0800 45.0100 180.0000 47.1900 ;
      RECT 0.0000 45.0100 19.8400 47.1900 ;
      RECT 160.0800 44.5900 179.3200 45.0100 ;
      RECT 0.6800 44.5900 19.8400 45.0100 ;
      RECT 160.0800 42.4100 180.0000 44.5900 ;
      RECT 0.0000 42.4100 19.8400 44.5900 ;
      RECT 160.0800 41.9900 179.3200 42.4100 ;
      RECT 0.6800 41.9900 19.8400 42.4100 ;
      RECT 160.0800 39.8100 180.0000 41.9900 ;
      RECT 0.0000 39.8100 19.8400 41.9900 ;
      RECT 160.0800 39.3900 179.3200 39.8100 ;
      RECT 0.6800 39.3900 19.8400 39.8100 ;
      RECT 160.0800 37.2100 180.0000 39.3900 ;
      RECT 0.0000 37.2100 19.8400 39.3900 ;
      RECT 160.0800 36.7900 179.3200 37.2100 ;
      RECT 0.6800 36.7900 19.8400 37.2100 ;
      RECT 160.0800 34.6100 180.0000 36.7900 ;
      RECT 0.0000 34.6100 19.8400 36.7900 ;
      RECT 160.0800 34.1900 179.3200 34.6100 ;
      RECT 0.6800 34.1900 19.8400 34.6100 ;
      RECT 160.0800 32.0100 180.0000 34.1900 ;
      RECT 0.0000 32.0100 19.8400 34.1900 ;
      RECT 160.0800 31.5900 179.3200 32.0100 ;
      RECT 0.6800 31.5900 19.8400 32.0100 ;
      RECT 160.0800 29.4100 180.0000 31.5900 ;
      RECT 0.0000 29.4100 19.8400 31.5900 ;
      RECT 160.0800 28.9900 179.3200 29.4100 ;
      RECT 0.6800 28.9900 19.8400 29.4100 ;
      RECT 160.0800 26.8100 180.0000 28.9900 ;
      RECT 0.0000 26.8100 19.8400 28.9900 ;
      RECT 160.0800 26.3900 179.3200 26.8100 ;
      RECT 0.6800 26.3900 19.8400 26.8100 ;
      RECT 160.0800 24.2100 180.0000 26.3900 ;
      RECT 0.0000 24.2100 19.8400 26.3900 ;
      RECT 160.0800 23.7900 179.3200 24.2100 ;
      RECT 0.6800 23.7900 19.8400 24.2100 ;
      RECT 160.0800 21.6100 180.0000 23.7900 ;
      RECT 0.0000 21.6100 19.8400 23.7900 ;
      RECT 160.0800 21.1900 179.3200 21.6100 ;
      RECT 0.6800 21.1900 19.8400 21.6100 ;
      RECT 160.0800 19.0100 180.0000 21.1900 ;
      RECT 0.0000 19.0100 19.8400 21.1900 ;
      RECT 160.0800 18.5900 179.3200 19.0100 ;
      RECT 0.6800 18.5900 19.8400 19.0100 ;
      RECT 160.0800 16.4100 180.0000 18.5900 ;
      RECT 0.0000 16.4100 19.8400 18.5900 ;
      RECT 160.0800 15.9900 179.3200 16.4100 ;
      RECT 0.6800 15.9900 19.8400 16.4100 ;
      RECT 158.0800 14.8400 158.7600 165.1600 ;
      RECT 154.3750 14.8400 156.7600 165.1600 ;
      RECT 152.3750 14.8400 153.0550 165.1600 ;
      RECT 148.6700 14.8400 151.0550 165.1600 ;
      RECT 146.6700 14.8400 147.3500 165.1600 ;
      RECT 142.9650 14.8400 145.3500 165.1600 ;
      RECT 140.9650 14.8400 141.6450 165.1600 ;
      RECT 137.2600 14.8400 139.6450 165.1600 ;
      RECT 135.2600 14.8400 135.9400 165.1600 ;
      RECT 131.5550 14.8400 133.9400 165.1600 ;
      RECT 129.5550 14.8400 130.2350 165.1600 ;
      RECT 125.8500 14.8400 128.2350 165.1600 ;
      RECT 123.8500 14.8400 124.5300 165.1600 ;
      RECT 120.1450 14.8400 122.5300 165.1600 ;
      RECT 118.1450 14.8400 118.8250 165.1600 ;
      RECT 114.4400 14.8400 116.8250 165.1600 ;
      RECT 112.4400 14.8400 113.1200 165.1600 ;
      RECT 108.7350 14.8400 111.1200 165.1600 ;
      RECT 106.7350 14.8400 107.4150 165.1600 ;
      RECT 103.0300 14.8400 105.4150 165.1600 ;
      RECT 101.0300 14.8400 101.7100 165.1600 ;
      RECT 97.3250 14.8400 99.7100 165.1600 ;
      RECT 95.3250 14.8400 96.0050 165.1600 ;
      RECT 91.6200 14.8400 94.0050 165.1600 ;
      RECT 89.6200 14.8400 90.3000 165.1600 ;
      RECT 85.9150 14.8400 88.3000 165.1600 ;
      RECT 83.9150 14.8400 84.5950 165.1600 ;
      RECT 80.2100 14.8400 82.5950 165.1600 ;
      RECT 78.2100 14.8400 78.8900 165.1600 ;
      RECT 74.5050 14.8400 76.8900 165.1600 ;
      RECT 72.5050 14.8400 73.1850 165.1600 ;
      RECT 68.8000 14.8400 71.1850 165.1600 ;
      RECT 66.8000 14.8400 67.4800 165.1600 ;
      RECT 63.0950 14.8400 65.4800 165.1600 ;
      RECT 61.0950 14.8400 61.7750 165.1600 ;
      RECT 57.3900 14.8400 59.7750 165.1600 ;
      RECT 55.3900 14.8400 56.0700 165.1600 ;
      RECT 51.6850 14.8400 54.0700 165.1600 ;
      RECT 49.6850 14.8400 50.3650 165.1600 ;
      RECT 45.9800 14.8400 48.3650 165.1600 ;
      RECT 43.9800 14.8400 44.6600 165.1600 ;
      RECT 40.2750 14.8400 42.6600 165.1600 ;
      RECT 38.2750 14.8400 38.9550 165.1600 ;
      RECT 34.5700 14.8400 36.9550 165.1600 ;
      RECT 32.5700 14.8400 33.2500 165.1600 ;
      RECT 28.8650 14.8400 31.2500 165.1600 ;
      RECT 26.8650 14.8400 27.5450 165.1600 ;
      RECT 23.1600 14.8400 25.5450 165.1600 ;
      RECT 21.1600 14.8400 21.8400 165.1600 ;
      RECT 0.0000 14.8400 19.8400 15.9900 ;
      RECT 160.0800 14.6750 180.0000 15.9900 ;
      RECT 154.3750 14.6750 158.7600 14.8400 ;
      RECT 148.6700 14.6750 153.0550 14.8400 ;
      RECT 142.9650 14.6750 147.3500 14.8400 ;
      RECT 137.2600 14.6750 141.6450 14.8400 ;
      RECT 131.5550 14.6750 135.9400 14.8400 ;
      RECT 125.8500 14.6750 130.2350 14.8400 ;
      RECT 120.1450 14.6750 124.5300 14.8400 ;
      RECT 114.4400 14.6750 118.8250 14.8400 ;
      RECT 108.7350 14.6750 113.1200 14.8400 ;
      RECT 103.0300 14.6750 107.4150 14.8400 ;
      RECT 97.3250 14.6750 101.7100 14.8400 ;
      RECT 91.6200 14.6750 96.0050 14.8400 ;
      RECT 85.9150 14.6750 90.3000 14.8400 ;
      RECT 80.2100 14.6750 84.5950 14.8400 ;
      RECT 74.5050 14.6750 78.8900 14.8400 ;
      RECT 68.8000 14.6750 73.1850 14.8400 ;
      RECT 63.0950 14.6750 67.4800 14.8400 ;
      RECT 57.3900 14.6750 61.7750 14.8400 ;
      RECT 51.6850 14.6750 56.0700 14.8400 ;
      RECT 45.9800 14.6750 50.3650 14.8400 ;
      RECT 40.2750 14.6750 44.6600 14.8400 ;
      RECT 34.5700 14.6750 38.9550 14.8400 ;
      RECT 28.8650 14.6750 33.2500 14.8400 ;
      RECT 23.1600 14.6750 27.5450 14.8400 ;
      RECT 0.0000 14.6750 21.8400 14.8400 ;
      RECT 0.0000 13.8100 180.0000 14.6750 ;
      RECT 0.6800 13.3900 179.3200 13.8100 ;
      RECT 0.0000 11.2100 180.0000 13.3900 ;
      RECT 0.6800 10.7900 179.3200 11.2100 ;
      RECT 0.0000 8.6100 180.0000 10.7900 ;
      RECT 0.6800 8.1900 179.3200 8.6100 ;
      RECT 0.0000 0.0000 180.0000 8.1900 ;
  END
END sram_w16_in

END LIBRARY
